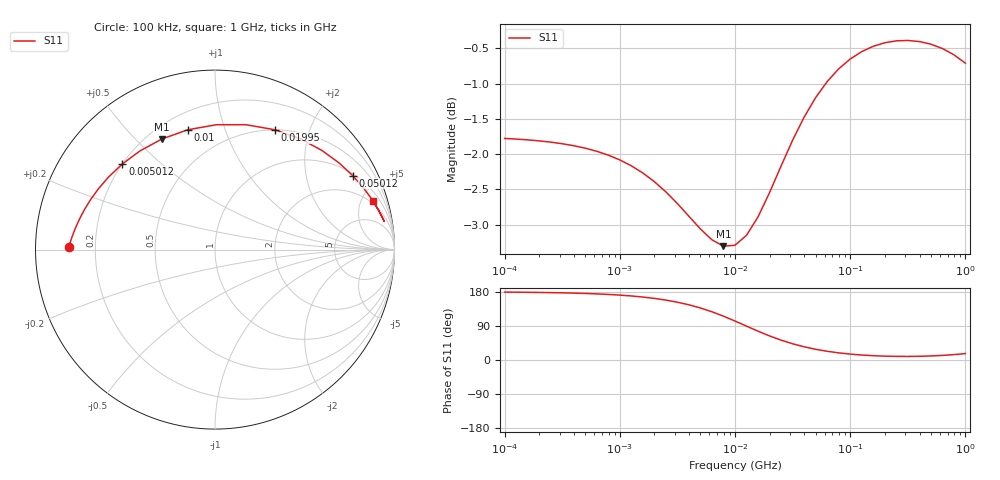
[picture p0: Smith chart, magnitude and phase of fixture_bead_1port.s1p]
# Hz S RI R 50
! test-double ferrite bead (R peaks ~300 MHz), for regression only
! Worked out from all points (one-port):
!   41 points, 100 kHz to 1 GHz, reference 50 ohm
!   lowest |S11| = -3.3 dB at 7.943 MHz (marker M1), VSWR 5.32, Z = 12.9 + j29.9 ohm
!   |S11| at or under -10 dB: nowhere
!   S11 on the Smith chart (normalised r, x): 100 kHz: 0.10, +0.01; 5.012 MHz: 0.20, +0.38; 10 MHz: 0.30, +0.75; 19.95 MHz: 0.50, +1.50; 50.12 MHz: 1.08, +3.68; 1 GHz: 1.75, +6.23
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100000  -0.8148 0.0124
316228  -0.8069 0.0389
630957  -0.7943 0.0767
1000000  -0.7777 0.1197
1584890  -0.7478 0.1845
1995260  -0.7245 0.2276
2511890  -0.6929 0.2787
3162280  -0.65 0.3382
3981070  -0.5924 0.4051
5011870  -0.5162 0.4772
6309570  -0.4179 0.5499
7943280  -0.2959 0.6162
1e7  -0.152 0.6675
1.25893e7  0.00781 0.6957
1.58489e7  0.1732 0.6958
1.99526e7  0.3323 0.6679
2.51189e7  0.4752 0.6173
3.16228e7  0.5958 0.5524
3.98107e7  0.6925 0.4818
5.01187e7  0.7671 0.4126
6.30957e7  0.823 0.3493
7.94328e7  0.864 0.2945
1.25893e8  0.9143 0.2134
1.99526e8  0.9375 0.1686
3.16228e8  0.9432 0.1565
5.01187e8  0.934 0.1758
6.30957e8  0.9227 0.1978
1e9  0.8812 0.2688
